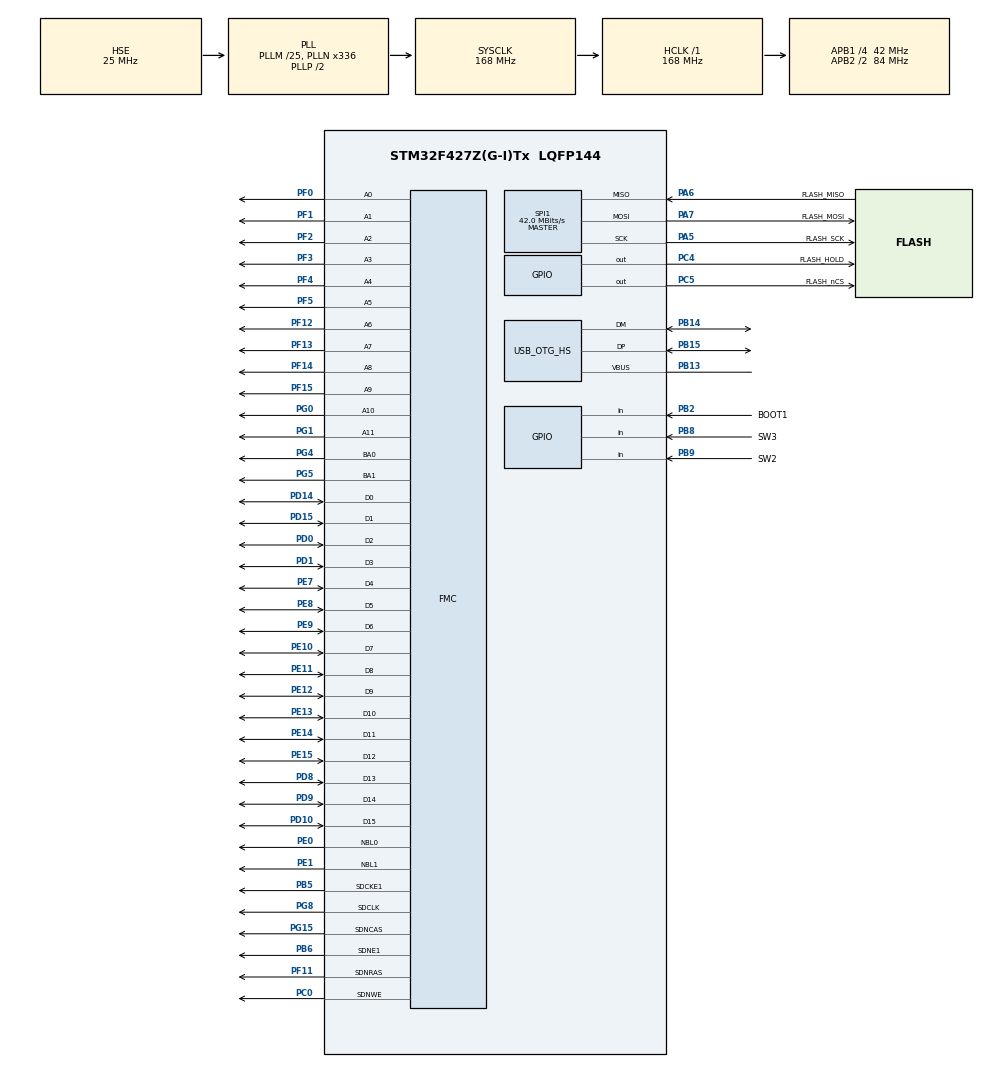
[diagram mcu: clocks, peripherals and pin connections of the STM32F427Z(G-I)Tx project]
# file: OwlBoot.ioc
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FMC.CASLatency1=FMC_SDRAM_CAS_LATENCY_3
FMC.ExitSelfRefreshDelay1=6
FMC.LoadToActiveDelay1=2
FMC.RCDDelay1=2
FMC.RPDelay1=2
FMC.RPDelay2=2
FMC.ReadBurst1=FMC_SDRAM_RBURST_ENABLE
FMC.ReadBurst2=FMC_SDRAM_RBURST_ENABLE
FMC.ReadPipeDelay1=FMC_SDRAM_RPIPE_DELAY_0
FMC.RowCycleDelay1=6
FMC.RowCycleDelay2=6
FMC.SDClockPeriod1=FMC_SDRAM_CLOCK_PERIOD_2
FMC.SDClockPeriod2=FMC_SDRAM_CLOCK_PERIOD_2
FMC.SelfRefreshTime1=4
FMC.WriteRecoveryTime1=2
Mcu.Family=STM32F4
Mcu.Name=STM32F427Z(G-I)Tx
Mcu.Package=LQFP144
NVIC.OTG_HS_IRQn=true\:8\:0\:true\:false\:true\:true
NVIC.PriorityGroup=NVIC_PRIORITYGROUP_4
PA13.Mode=Trace_Asynchronous_SW
PA13.Signal=SYS_JTMS-SWDIO
PA14.Mode=Trace_Asynchronous_SW
PA14.Signal=SYS_JTCK-SWCLK
PA5.GPIO_Label=FLASH_SCK
PA5.Mode=Full_Duplex_Master
PA5.Signal=SPI1_SCK
PA6.GPIO_Label=FLASH_MISO
PA6.Mode=Full_Duplex_Master
PA6.Signal=SPI1_MISO
PA7.GPIO_Label=FLASH_MOSI
PA7.Mode=Full_Duplex_Master
PA7.Signal=SPI1_MOSI
PB13.Mode=Activate_VBUS_FS
PB13.Signal=USB_OTG_HS_VBUS
PB14.Mode=Device_Only_FS
PB14.Signal=USB_OTG_HS_DM
PB15.Mode=Device_Only_FS
PB15.Signal=USB_OTG_HS_DP
PB2/BOOT1.GPIO_Label=BOOT1
PB2/BOOT1.GPIO_PuPd=GPIO_PULLUP
PB2/BOOT1.Signal=GPIO_Input
PB3.Mode=Trace_Asynchronous_SW
PB3.Signal=SYS_JTDO-SWO
PB5.Mode=SdramChipSelect2_1
PB5.Signal=FMC_SDCKE1
PB6.Mode=SdramChipSelect2_1
PB6.Signal=FMC_SDNE1
PB8.GPIO_Label=SW3
PB8.Signal=GPIO_Input
PB9.GPIO_Label=SW2
PB9.Signal=GPIO_Input
PC0.Signal=FMC_SDNWE
PC4.GPIO_Label=FLASH_HOLD
PC4.Signal=GPIO_Output
PC5.GPIO_Label=FLASH_nCS
PC5.Signal=GPIO_Output
PD0.Signal=FMC_D2_DA2
PD1.Signal=FMC_D3_DA3
PD10.Signal=FMC_D15_DA15
PD14.Signal=FMC_D0_DA0
PD15.Signal=FMC_D1_DA1
PD8.Signal=FMC_D13_DA13
PD9.Signal=FMC_D14_DA14
PE0.Signal=FMC_NBL0
PE1.Signal=FMC_NBL1
PE10.Signal=FMC_D7_DA7
PE11.Signal=FMC_D8_DA8
PE12.Signal=FMC_D9_DA9
PE13.Signal=FMC_D10_DA10
PE14.Signal=FMC_D11_DA11
PE15.Signal=FMC_D12_DA12
PE7.Signal=FMC_D4_DA4
PE8.Signal=FMC_D5_DA5
PE9.Signal=FMC_D6_DA6
PF0.Signal=FMC_A0
PF1.Signal=FMC_A1
PF11.Signal=FMC_SDNRAS
PF12.Signal=FMC_A6
PF13.Signal=FMC_A7
PF14.Signal=FMC_A8
PF15.Signal=FMC_A9
PF2.Signal=FMC_A2
PF3.Signal=FMC_A3
PF4.Signal=FMC_A4
PF5.Signal=FMC_A5
PG0.Signal=FMC_A10
PG1.Signal=FMC_A11
PG15.Signal=FMC_SDNCAS
PG4.Signal=FMC_A14_BA0
PG5.Signal=FMC_A15_BA1
PG8.Signal=FMC_SDCLK
PH0/OSC_IN.Mode=HSE-External-Oscillator
PH0/OSC_IN.Signal=RCC_OSC_IN
PH1/OSC_OUT.Mode=HSE-External-Oscillator
PH1/OSC_OUT.Signal=RCC_OSC_OUT
ProjectManager.HeapSize=0x200
ProjectManager.StackSize=0x400
ProjectManager.TargetToolchain=MDK-ARM V5
RCC.48MHZClocksFreq_Value=48000000
RCC.AHBFreq_Value=168000000
RCC.APB1CLKDivider=RCC_HCLK_DIV4
RCC.APB1Freq_Value=42000000
RCC.APB1TimFreq_Value=84000000
RCC.APB2CLKDivider=RCC_HCLK_DIV2
RCC.APB2Freq_Value=84000000
RCC.APB2TimFreq_Value=168000000
RCC.CortexFreq_Value=168000000
RCC.HCLKFreq_Value=168000000
RCC.HSE_VALUE=25000000
RCC.HSI_VALUE=16000000
RCC.LSE_VALUE=32768
RCC.PLLM=25
RCC.PLLN=336
RCC.PLLQ=7
RCC.PLLSAIN=100
RCC.SYSCLKFreq_VALUE=168000000
RCC.SYSCLKSource=RCC_SYSCLKSOURCE_PLLCLK
RCC.USBFreq_Value=48000000
RCC.VCOOutputFreq_Value=336000000
SH.FMC_A0.0=FMC_A0,12b-sda1
SH.FMC_A1.0=FMC_A1,12b-sda1
SH.FMC_A10.0=FMC_A10,12b-sda1
SH.FMC_A11.0=FMC_A11,12b-sda1
SH.FMC_A14_BA0.0=FMC_BA0,FourSdramBanks1
SH.FMC_A15_BA1.0=FMC_BA1,FourSdramBanks1
SH.FMC_A2.0=FMC_A2,12b-sda1
SH.FMC_A3.0=FMC_A3,12b-sda1
SH.FMC_A4.0=FMC_A4,12b-sda1
SH.FMC_A5.0=FMC_A5,12b-sda1
SH.FMC_A6.0=FMC_A6,12b-sda1
SH.FMC_A7.0=FMC_A7,12b-sda1
SH.FMC_A8.0=FMC_A8,12b-sda1
SH.FMC_A9.0=FMC_A9,12b-sda1
SH.FMC_D0_DA0.0=FMC_D0,sd-16b-d1
SH.FMC_D10_DA10.0=FMC_D10,sd-16b-d1
SH.FMC_D11_DA11.0=FMC_D11,sd-16b-d1
SH.FMC_D12_DA12.0=FMC_D12,sd-16b-d1
SH.FMC_D13_DA13.0=FMC_D13,sd-16b-d1
SH.FMC_D14_DA14.0=FMC_D14,sd-16b-d1
SH.FMC_D15_DA15.0=FMC_D15,sd-16b-d1
SH.FMC_D1_DA1.0=FMC_D1,sd-16b-d1
SH.FMC_D2_DA2.0=FMC_D2,sd-16b-d1
SH.FMC_D3_DA3.0=FMC_D3,sd-16b-d1
SH.FMC_D4_DA4.0=FMC_D4,sd-16b-d1
SH.FMC_D5_DA5.0=FMC_D5,sd-16b-d1
SH.FMC_D6_DA6.0=FMC_D6,sd-16b-d1
SH.FMC_D7_DA7.0=FMC_D7,sd-16b-d1
SH.FMC_D8_DA8.0=FMC_D8,sd-16b-d1
SH.FMC_D9_DA9.0=FMC_D9,sd-16b-d1
SH.FMC_NBL0.0=FMC_NBL0,Sd2ByteEnable1
SH.FMC_NBL1.0=FMC_NBL1,Sd2ByteEnable1
SH.FMC_SDCLK.0=FMC_SDCLK,12b-sda1
SH.FMC_SDNCAS.0=FMC_SDNCAS,12b-sda1
SH.FMC_SDNRAS.0=FMC_SDNRAS,12b-sda1
SH.FMC_SDNWE.0=FMC_SDNWE,12b-sda1
SPI1.CalculateBaudRate=42.0 MBits/s
SPI1.Direction=SPI_DIRECTION_2LINES
SPI1.Mode=SPI_MODE_MASTER
SPI1.VirtualType=VM_MASTER
USB_DEVICE.CLASS_NAME_HS=AUDIO
USB_DEVICE.MANUFACTURER_STRING-AUDIO_HS=Rebel Technology
USB_DEVICE.PID_AUDIO_HS=0xDADA
USB_DEVICE.PRODUCT_STRING_AUDIO_HS=OWL-BOOT
USB_DEVICE.SERIALNUMBER_STRING_AUDIO_HS=00000000010D
USB_DEVICE.VID-AUDIO_HS=0x1209
USB_DEVICE.VirtualMode-AUDIO_HS=Audio
USB_DEVICE.VirtualModeHS=Audio_HS
USB_OTG_HS.VirtualMode-Device_Only_FS=Device_Only_FS
VP_USB_DEVICE_VS_USB_DEVICE_AUDIO_HS.Mode=AUDIO_HS
board=OwlBoot

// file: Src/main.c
/**
  ******************************************************************************
  * @file           : main.c
  * @brief          : Main program body
  ******************************************************************************
  * This notice applies to any and all portions of this file
  * that are not between comment pairs USER CODE BEGIN and
  * USER CODE END. Other portions of this file, whether
  * inserted by the user or by software development tools
  * are owned by their respective copyright owners.
  *
  * Copyright (c) 2018 STMicroelectronics International N.V.
  * All rights reserved.
  *
  * Redistribution and use in source and binary forms, with or without
  * modification, are permitted, provided that the following conditions are met:
  *
  * 1. Redistribution of source code must retain the above copyright notice,
  *    this list of conditions and the following disclaimer.
  * 2. Redistributions in binary form must reproduce the above copyright notice,
  *    this list of conditions and the following disclaimer in the documentation
  *    and/or other materials provided with the distribution.
  * 3. Neither the name of STMicroelectronics nor the names of other
  *    contributors to this software may be used to endorse or promote products
  *    derived from this software without specific written permission.
  * 4. This software, including modifications and/or derivative works of this
  *    software, must execute solely and exclusively on microcontroller or
  *    microprocessor devices manufactured by or for STMicroelectronics.
  * 5. Redistribution and use of this software other than as permitted under
  *    this license is void and will automatically terminate your rights under
  *    this license.
  *
  * THIS SOFTWARE IS PROVIDED BY STMICROELECTRONICS AND CONTRIBUTORS "AS IS"
  * AND ANY EXPRESS, IMPLIED OR STATUTORY WARRANTIES, INCLUDING, BUT NOT
  * LIMITED TO, THE IMPLIED WARRANTIES OF MERCHANTABILITY, FITNESS FOR A
  * PARTICULAR PURPOSE AND NON-INFRINGEMENT OF THIRD PARTY INTELLECTUAL PROPERTY
  * RIGHTS ARE DISCLAIMED TO THE FULLEST EXTENT PERMITTED BY LAW. IN NO EVENT
  * SHALL STMICROELECTRONICS OR CONTRIBUTORS BE LIABLE FOR ANY DIRECT, INDIRECT,
  * INCIDENTAL, SPECIAL, EXEMPLARY, OR CONSEQUENTIAL DAMAGES (INCLUDING, BUT NOT
  * LIMITED TO, PROCUREMENT OF SUBSTITUTE GOODS OR SERVICES; LOSS OF USE, DATA,
  * OR PROFITS; OR BUSINESS INTERRUPTION) HOWEVER CAUSED AND ON ANY THEORY OF
  * LIABILITY, WHETHER IN CONTRACT, STRICT LIABILITY, OR TORT (INCLUDING
  * NEGLIGENCE OR OTHERWISE) ARISING IN ANY WAY OUT OF THE USE OF THIS SOFTWARE,
  * EVEN IF ADVISED OF THE POSSIBILITY OF SUCH DAMAGE.
  *
  ******************************************************************************
  */
#include "main.h"
#include "stm32f4xx_hal.h"
#include "usb_device.h"

/* USER CODE BEGIN Includes */
#include "eepromcontrol.h"

/* USER CODE END Includes */

SPI_HandleTypeDef hspi1;

SDRAM_HandleTypeDef hsdram1;

/* USER CODE BEGIN PV */
/* Private variables ---------------------------------------------------------*/

/* USER CODE END PV */

void SystemClock_Config(void);
static void MX_GPIO_Init(void);
static void MX_FMC_Init(void);
static void MX_SPI1_Init(void);

/* USER CODE BEGIN PFP */
/* Private function prototypes -----------------------------------------------*/

void setup();
void SDRAM_Initialization_Sequence(SDRAM_HandleTypeDef *hsdram);
void loop(void);

typedef  void (*pFunction)(void);
#define APPLICATION_ADDRESS        ADDR_FLASH_SECTOR_4

static int testMagic(){
  const uint32_t bootloaderMagicNumber = 0xDADAB007;
  const uint32_t* bootloaderMagicAddress = (uint32_t*)0x2000FFF0;
  return *bootloaderMagicAddress == bootloaderMagicNumber;
}

static int testButton(){
  return !(BOOT1_GPIO_Port->IDR & BOOT1_Pin);
}

static int testNoProgram(){
  return ((*(__IO uint32_t*)APPLICATION_ADDRESS) & 0x2FFE0000 ) != 0x20000000;
  /* Check Vector Table: Test if valid stack pointer is programmed at APPLICATION_ADDRESS */
}

/* USER CODE END PFP */

int main(void)
{

  /* MCU Configuration----------------------------------------------------------*/

  /* Reset of all peripherals, Initializes the Flash interface and the Systick. */
  HAL_Init();

  /* Configure the system clock */
  SystemClock_Config();

  /* USER CODE BEGIN SysInit */

  MX_GPIO_Init();

  if(testButton() || testMagic() || testNoProgram()){
    // we're going to boot
  }else{
    // jump to application code

    /* Disable all interrupts */
    RCC->CIR = 0x00000000;

    /* Jump to user application */
    uint32_t JumpAddress = *(__IO uint32_t*) (APPLICATION_ADDRESS + 4);
    pFunction jumpToApplication = (pFunction) JumpAddress;
    /* Initialize user application's Stack Pointer */
    __set_MSP(*(__IO uint32_t*) APPLICATION_ADDRESS);
    jumpToApplication();
    for(;;);
  }

  /* USER CODE END SysInit */

  /* Initialize all configured peripherals */
  MX_GPIO_Init();
  MX_FMC_Init();
  MX_SPI1_Init();
  MX_USB_DEVICE_Init();
  /* USER CODE BEGIN 2 */

  SDRAM_Initialization_Sequence(&hsdram1);

  // Initialise
  setup();

  /* USER CODE END 2 */

  /* Infinite loop */
  /* USER CODE BEGIN WHILE */
  while (1)
  {
    loop();
  /* USER CODE END WHILE */

  }

}

void SystemClock_Config(void)
{

  RCC_OscInitTypeDef RCC_OscInitStruct;
  RCC_ClkInitTypeDef RCC_ClkInitStruct;

    /**Configure the main internal regulator output voltage
    */
  __HAL_RCC_PWR_CLK_ENABLE();

  __HAL_PWR_VOLTAGESCALING_CONFIG(PWR_REGULATOR_VOLTAGE_SCALE1);

    /**Initializes the CPU, AHB and APB busses clocks
    */
  RCC_OscInitStruct.OscillatorType = RCC_OSCILLATORTYPE_HSE;
  RCC_OscInitStruct.HSEState = RCC_HSE_ON;
  RCC_OscInitStruct.PLL.PLLState = RCC_PLL_ON;
  RCC_OscInitStruct.PLL.PLLSource = RCC_PLLSOURCE_HSE;
  RCC_OscInitStruct.PLL.PLLM = 25;
  RCC_OscInitStruct.PLL.PLLN = 336;
  RCC_OscInitStruct.PLL.PLLP = RCC_PLLP_DIV2;
  RCC_OscInitStruct.PLL.PLLQ = 7;
  if (HAL_RCC_OscConfig(&RCC_OscInitStruct) != HAL_OK)
  {
    _Error_Handler(__FILE__, __LINE__);
  }

    /**Initializes the CPU, AHB and APB busses clocks
    */
  RCC_ClkInitStruct.ClockType = RCC_CLOCKTYPE_HCLK|RCC_CLOCKTYPE_SYSCLK
                              |RCC_CLOCKTYPE_PCLK1|RCC_CLOCKTYPE_PCLK2;
  RCC_ClkInitStruct.SYSCLKSource = RCC_SYSCLKSOURCE_PLLCLK;
  RCC_ClkInitStruct.AHBCLKDivider = RCC_SYSCLK_DIV1;
  RCC_ClkInitStruct.APB1CLKDivider = RCC_HCLK_DIV4;
  RCC_ClkInitStruct.APB2CLKDivider = RCC_HCLK_DIV2;

  if (HAL_RCC_ClockConfig(&RCC_ClkInitStruct, FLASH_LATENCY_5) != HAL_OK)
  {
    _Error_Handler(__FILE__, __LINE__);
  }

    /**Configure the Systick interrupt time
    */
  HAL_SYSTICK_Config(HAL_RCC_GetHCLKFreq()/1000);

    /**Configure the Systick
    */
  HAL_SYSTICK_CLKSourceConfig(SYSTICK_CLKSOURCE_HCLK);

  /* SysTick_IRQn interrupt configuration */
  HAL_NVIC_SetPriority(SysTick_IRQn, 0, 0);
}

/* SPI1 init function */
static void MX_SPI1_Init(void)
{

  /* SPI1 parameter configuration*/
  hspi1.Instance = SPI1;
  hspi1.Init.Mode = SPI_MODE_MASTER;
  hspi1.Init.Direction = SPI_DIRECTION_2LINES;
  hspi1.Init.DataSize = SPI_DATASIZE_8BIT;
  hspi1.Init.CLKPolarity = SPI_POLARITY_LOW;
  hspi1.Init.CLKPhase = SPI_PHASE_1EDGE;
  hspi1.Init.NSS = SPI_NSS_SOFT;
  hspi1.Init.BaudRatePrescaler = SPI_BAUDRATEPRESCALER_2;
  hspi1.Init.FirstBit = SPI_FIRSTBIT_MSB;
  hspi1.Init.TIMode = SPI_TIMODE_DISABLE;
  hspi1.Init.CRCCalculation = SPI_CRCCALCULATION_DISABLE;
  hspi1.Init.CRCPolynomial = 10;
  if (HAL_SPI_Init(&hspi1) != HAL_OK)
  {
    _Error_Handler(__FILE__, __LINE__);
  }

}

/* FMC initialization function */
static void MX_FMC_Init(void)
{
  FMC_SDRAM_TimingTypeDef SdramTiming;

  /** Perform the SDRAM1 memory initialization sequence
  */
  hsdram1.Instance = FMC_SDRAM_DEVICE;
  /* hsdram1.Init */
  hsdram1.Init.SDBank = FMC_SDRAM_BANK2;
  hsdram1.Init.ColumnBitsNumber = FMC_SDRAM_COLUMN_BITS_NUM_8;
  hsdram1.Init.RowBitsNumber = FMC_SDRAM_ROW_BITS_NUM_12;
  hsdram1.Init.MemoryDataWidth = FMC_SDRAM_MEM_BUS_WIDTH_16;
  hsdram1.Init.InternalBankNumber = FMC_SDRAM_INTERN_BANKS_NUM_4;
  hsdram1.Init.CASLatency = FMC_SDRAM_CAS_LATENCY_3;
  hsdram1.Init.WriteProtection = FMC_SDRAM_WRITE_PROTECTION_DISABLE;
  hsdram1.Init.SDClockPeriod = FMC_SDRAM_CLOCK_PERIOD_2;
  hsdram1.Init.ReadBurst = FMC_SDRAM_RBURST_ENABLE;
  hsdram1.Init.ReadPipeDelay = FMC_SDRAM_RPIPE_DELAY_0;
  /* SdramTiming */
  SdramTiming.LoadToActiveDelay = 2;
  SdramTiming.ExitSelfRefreshDelay = 6;
  SdramTiming.SelfRefreshTime = 4;
  SdramTiming.RowCycleDelay = 6;
  SdramTiming.WriteRecoveryTime = 2;
  SdramTiming.RPDelay = 2;
  SdramTiming.RCDDelay = 2;

  if (HAL_SDRAM_Init(&hsdram1, &SdramTiming) != HAL_OK)
  {
    _Error_Handler(__FILE__, __LINE__);
  }

}

/** Configure pins as
        * Analog
        * Input
        * Output
        * EVENT_OUT
        * EXTI
        * Free pins are configured automatically as Analog (this feature is enabled through
        * the Code Generation settings)
*/
static void MX_GPIO_Init(void)
{

  GPIO_InitTypeDef GPIO_InitStruct;

  /* GPIO Ports Clock Enable */
  __HAL_RCC_GPIOE_CLK_ENABLE();
  __HAL_RCC_GPIOC_CLK_ENABLE();
  __HAL_RCC_GPIOF_CLK_ENABLE();
  __HAL_RCC_GPIOH_CLK_ENABLE();
  __HAL_RCC_GPIOA_CLK_ENABLE();
  __HAL_RCC_GPIOB_CLK_ENABLE();
  __HAL_RCC_GPIOG_CLK_ENABLE();
  __HAL_RCC_GPIOD_CLK_ENABLE();

  /*Configure GPIO pin Output Level */
  HAL_GPIO_WritePin(GPIOA, LED1_Pin|LED2_Pin, GPIO_PIN_RESET);

  /*Configure GPIO pin Output Level */
  HAL_GPIO_WritePin(GPIOC, FLASH_HOLD_Pin|FLASH_nCS_Pin, GPIO_PIN_RESET);

  /*Configure GPIO pins : PE2 PE3 PE4 PE5
                           PE6 */
  GPIO_InitStruct.Pin = GPIO_PIN_2|GPIO_PIN_3|GPIO_PIN_4|GPIO_PIN_5
                          |GPIO_PIN_6;
  GPIO_InitStruct.Mode = GPIO_MODE_ANALOG;
  GPIO_InitStruct.Pull = GPIO_NOPULL;
  HAL_GPIO_Init(GPIOE, &GPIO_InitStruct);

  /*Configure GPIO pins : PC13 PC14 PC15 PC1
                           PC2 PC3 PC6 PC7
                           PC8 PC9 PC10 PC11
                           PC12 */
  GPIO_InitStruct.Pin = GPIO_PIN_13|GPIO_PIN_14|GPIO_PIN_15|GPIO_PIN_1
                          |GPIO_PIN_2|GPIO_PIN_3|GPIO_PIN_6|GPIO_PIN_7
                          |GPIO_PIN_8|GPIO_PIN_9|GPIO_PIN_10|GPIO_PIN_11
                          |GPIO_PIN_12;
  GPIO_InitStruct.Mode = GPIO_MODE_ANALOG;
  GPIO_InitStruct.Pull = GPIO_NOPULL;
  HAL_GPIO_Init(GPIOC, &GPIO_InitStruct);

  /*Configure GPIO pins : PF6 PF7 PF8 PF9
                           PF10 */
  GPIO_InitStruct.Pin = GPIO_PIN_6|GPIO_PIN_7|GPIO_PIN_8|GPIO_PIN_9
                          |GPIO_PIN_10;
  GPIO_InitStruct.Mode = GPIO_MODE_ANALOG;
  GPIO_InitStruct.Pull = GPIO_NOPULL;
  HAL_GPIO_Init(GPIOF, &GPIO_InitStruct);

  /*Configure GPIO pins : LED1_Pin LED2_Pin */
  GPIO_InitStruct.Pin = LED1_Pin|LED2_Pin;
  GPIO_InitStruct.Mode = GPIO_MODE_OUTPUT_PP;
  GPIO_InitStruct.Pull = GPIO_NOPULL;
  GPIO_InitStruct.Speed = GPIO_SPEED_FREQ_LOW;
  HAL_GPIO_Init(GPIOA, &GPIO_InitStruct);

  /*Configure GPIO pins : PA2 PA3 PA4 PA8
                           PA9 PA10 PA11 PA12
                           PA15 */
  GPIO_InitStruct.Pin = GPIO_PIN_2|GPIO_PIN_3|GPIO_PIN_4|GPIO_PIN_8
                          |GPIO_PIN_9|GPIO_PIN_10|GPIO_PIN_11|GPIO_PIN_12
                          |GPIO_PIN_15;
  GPIO_InitStruct.Mode = GPIO_MODE_ANALOG;
  GPIO_InitStruct.Pull = GPIO_NOPULL;
  HAL_GPIO_Init(GPIOA, &GPIO_InitStruct);

  /*Configure GPIO pins : FLASH_HOLD_Pin FLASH_nCS_Pin */
  GPIO_InitStruct.Pin = FLASH_HOLD_Pin|FLASH_nCS_Pin;
  GPIO_InitStruct.Mode = GPIO_MODE_OUTPUT_PP;
  GPIO_InitStruct.Pull = GPIO_NOPULL;
  GPIO_InitStruct.Speed = GPIO_SPEED_FREQ_LOW;
  HAL_GPIO_Init(GPIOC, &GPIO_InitStruct);

  /*Configure GPIO pins : PB0 PB1 PB10 PB11
                           PB12 PB4 PB7 */
  GPIO_InitStruct.Pin = GPIO_PIN_0|GPIO_PIN_1|GPIO_PIN_10|GPIO_PIN_11
                          |GPIO_PIN_12|GPIO_PIN_4|GPIO_PIN_7;
  GPIO_InitStruct.Mode = GPIO_MODE_ANALOG;
  GPIO_InitStruct.Pull = GPIO_NOPULL;
  HAL_GPIO_Init(GPIOB, &GPIO_InitStruct);

  /*Configure GPIO pin : BOOT1_Pin */
  GPIO_InitStruct.Pin = BOOT1_Pin;
  GPIO_InitStruct.Mode = GPIO_MODE_INPUT;
  GPIO_InitStruct.Pull = GPIO_PULLUP;
  HAL_GPIO_Init(BOOT1_GPIO_Port, &GPIO_InitStruct);

  /*Configure GPIO pins : PD11 PD12 PD13 PD2
                           PD3 PD4 PD5 PD6
                           PD7 */
  GPIO_InitStruct.Pin = GPIO_PIN_11|GPIO_PIN_12|GPIO_PIN_13|GPIO_PIN_2
                          |GPIO_PIN_3|GPIO_PIN_4|GPIO_PIN_5|GPIO_PIN_6
                          |GPIO_PIN_7;
  GPIO_InitStruct.Mode = GPIO_MODE_ANALOG;
  GPIO_InitStruct.Pull = GPIO_NOPULL;
  HAL_GPIO_Init(GPIOD, &GPIO_InitStruct);

  /*Configure GPIO pins : PG2 PG3 PG6 PG7
                           PG9 PG10 PG11 PG12
                           PG13 PG14 */
  GPIO_InitStruct.Pin = GPIO_PIN_2|GPIO_PIN_3|GPIO_PIN_6|GPIO_PIN_7
                          |GPIO_PIN_9|GPIO_PIN_10|GPIO_PIN_11|GPIO_PIN_12
                          |GPIO_PIN_13|GPIO_PIN_14;
  GPIO_InitStruct.Mode = GPIO_MODE_ANALOG;
  GPIO_InitStruct.Pull = GPIO_NOPULL;
  HAL_GPIO_Init(GPIOG, &GPIO_InitStruct);

  /*Configure GPIO pins : SW3_Pin SW2_Pin */
  GPIO_InitStruct.Pin = SW3_Pin|SW2_Pin;
  GPIO_InitStruct.Mode = GPIO_MODE_INPUT;
  GPIO_InitStruct.Pull = GPIO_NOPULL;
  HAL_GPIO_Init(GPIOB, &GPIO_InitStruct);

}

void _Error_Handler(char *file, int line)
{
  /* USER CODE BEGIN Error_Handler_Debug */
#ifdef DEBUG
  __asm__("BKPT");
#else
  NVIC_SystemReset();
#endif
  /* USER CODE END Error_Handler_Debug */
}

#ifdef  USE_FULL_ASSERT
/**
  * @brief  Reports the name of the source file and the source line number
  *         where the assert_param error has occurred.
  * @param  file: pointer to the source file name
  * @param  line: assert_param error line source number
  * @retval None
  */
void assert_failed(uint8_t* file, uint32_t line)
{
  /* USER CODE BEGIN 6 */
#ifdef DEBUG
  __asm__("BKPT");
#else
  NVIC_SystemReset();
#endif
  /* USER CODE END 6 */
}
#endif /* USE_FULL_ASSERT */

/************************ (C) COPYRIGHT STMicroelectronics *****END OF FILE****/
